VERSION 5.8 ;
BUSBITCHARS "[]" ;
DIVIDERCHAR "/" ;

UNITS
  DATABASE MICRONS 1000 ;
END UNITS

MANUFACTURINGGRID 0.001 ;

# ============================================================================
# ASAP5 / TSMC N5 Technology LEF
# Updated: 12 routing metals (M1-M12) + 11 via layers
# RC values calibrated to TSMC N5 5nm FinFET metal stack
#
# Metal Tiers:
#   Local (M1-M3):      28nm pitch, 14nm width, 36nm thick
#   Intermediate (M4-M6): 40nm pitch, 20nm width, 40nm thick
#   Semi-global (M7-M8): 80nm pitch, 40nm width, 60nm thick
#   Global (M9-M10):    160nm pitch, 80nm width, 100nm thick
#   Top power (M11-M12): 800nm pitch, 400nm width, 800nm thick
#
# RPERSQ = R_per_μm × Width_μm
# CPERSQDIST = C_per_μm / Width_μm (effective area capacitance)
# ============================================================================

# --- Local interconnect: M1-M3 ---

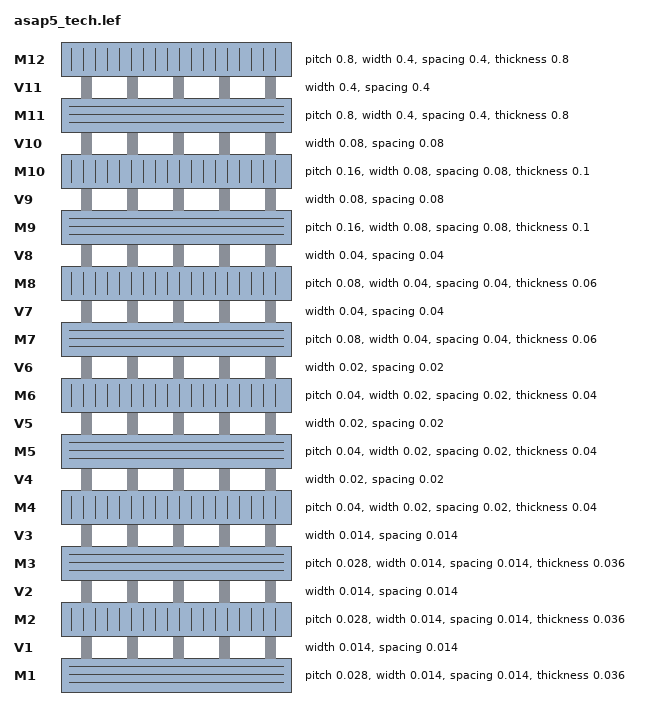
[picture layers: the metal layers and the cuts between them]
LAYER M1
  TYPE ROUTING ;
  DIRECTION HORIZONTAL ;
  PITCH 0.028 ;
  WIDTH 0.014 ;
  SPACING 0.014 ;
  RESISTANCE RPERSQ 0.560 ;
  CAPACITANCE CPERSQDIST 0.02000 ;
  THICKNESS 0.036 ;
END M1

LAYER V1
  TYPE CUT ;
  SPACING 0.014 ;
  WIDTH 0.014 ;
END V1

LAYER M2
  TYPE ROUTING ;
  DIRECTION VERTICAL ;
  PITCH 0.028 ;
  WIDTH 0.014 ;
  SPACING 0.014 ;
  RESISTANCE RPERSQ 3.150 ;
  CAPACITANCE CPERSQDIST 0.01929 ;
  THICKNESS 0.036 ;
END M2

LAYER V2
  TYPE CUT ;
  SPACING 0.014 ;
  WIDTH 0.014 ;
END V2

LAYER M3
  TYPE ROUTING ;
  DIRECTION HORIZONTAL ;
  PITCH 0.028 ;
  WIDTH 0.014 ;
  SPACING 0.014 ;
  RESISTANCE RPERSQ 1.386 ;
  CAPACITANCE CPERSQDIST 0.01571 ;
  THICKNESS 0.036 ;
END M3

LAYER V3
  TYPE CUT ;
  SPACING 0.014 ;
  WIDTH 0.014 ;
END V3

# --- Intermediate interconnect: M4-M6 ---

LAYER M4
  TYPE ROUTING ;
  DIRECTION VERTICAL ;
  PITCH 0.040 ;
  WIDTH 0.020 ;
  SPACING 0.020 ;
  RESISTANCE RPERSQ 2.340 ;
  CAPACITANCE CPERSQDIST 0.01000 ;
  THICKNESS 0.040 ;
END M4

LAYER V4
  TYPE CUT ;
  SPACING 0.020 ;
  WIDTH 0.020 ;
END V4

LAYER M5
  TYPE ROUTING ;
  DIRECTION HORIZONTAL ;
  PITCH 0.040 ;
  WIDTH 0.020 ;
  SPACING 0.020 ;
  RESISTANCE RPERSQ 1.040 ;
  CAPACITANCE CPERSQDIST 0.01300 ;
  THICKNESS 0.040 ;
END M5

LAYER V5
  TYPE CUT ;
  SPACING 0.020 ;
  WIDTH 0.020 ;
END V5

LAYER M6
  TYPE ROUTING ;
  DIRECTION VERTICAL ;
  PITCH 0.040 ;
  WIDTH 0.020 ;
  SPACING 0.020 ;
  RESISTANCE RPERSQ 0.320 ;
  CAPACITANCE CPERSQDIST 0.00800 ;
  THICKNESS 0.040 ;
END M6

LAYER V6
  TYPE CUT ;
  SPACING 0.020 ;
  WIDTH 0.020 ;
END V6

# --- Semi-global interconnect: M7-M8 ---

LAYER M7
  TYPE ROUTING ;
  DIRECTION HORIZONTAL ;
  PITCH 0.080 ;
  WIDTH 0.040 ;
  SPACING 0.040 ;
  RESISTANCE RPERSQ 0.440 ;
  CAPACITANCE CPERSQDIST 0.00425 ;
  THICKNESS 0.060 ;
END M7

LAYER V7
  TYPE CUT ;
  SPACING 0.040 ;
  WIDTH 0.040 ;
END V7

LAYER M8
  TYPE ROUTING ;
  DIRECTION VERTICAL ;
  PITCH 0.080 ;
  WIDTH 0.040 ;
  SPACING 0.040 ;
  RESISTANCE RPERSQ 0.440 ;
  CAPACITANCE CPERSQDIST 0.00425 ;
  THICKNESS 0.060 ;
END M8

LAYER V8
  TYPE CUT ;
  SPACING 0.040 ;
  WIDTH 0.040 ;
END V8

# --- Global interconnect: M9-M10 ---

LAYER M9
  TYPE ROUTING ;
  DIRECTION HORIZONTAL ;
  PITCH 0.160 ;
  WIDTH 0.080 ;
  SPACING 0.080 ;
  RESISTANCE RPERSQ 0.880 ;
  CAPACITANCE CPERSQDIST 0.00238 ;
  THICKNESS 0.100 ;
END M9

LAYER V9
  TYPE CUT ;
  SPACING 0.080 ;
  WIDTH 0.080 ;
END V9

LAYER M10
  TYPE ROUTING ;
  DIRECTION VERTICAL ;
  PITCH 0.160 ;
  WIDTH 0.080 ;
  SPACING 0.080 ;
  RESISTANCE RPERSQ 0.032 ;
  CAPACITANCE CPERSQDIST 0.00438 ;
  THICKNESS 0.100 ;
END M10

LAYER V10
  TYPE CUT ;
  SPACING 0.080 ;
  WIDTH 0.080 ;
END V10

# --- Top-level power: M11-M12 ---

LAYER M11
  TYPE ROUTING ;
  DIRECTION HORIZONTAL ;
  PITCH 0.800 ;
  WIDTH 0.400 ;
  SPACING 0.400 ;
  RESISTANCE RPERSQ 0.160 ;
  CAPACITANCE CPERSQDIST 0.00088 ;
  THICKNESS 0.800 ;
END M11

LAYER V11
  TYPE CUT ;
  SPACING 0.400 ;
  WIDTH 0.400 ;
END V11

LAYER M12
  TYPE ROUTING ;
  DIRECTION VERTICAL ;
  PITCH 0.800 ;
  WIDTH 0.400 ;
  SPACING 0.400 ;
  RESISTANCE RPERSQ 0.160 ;
  CAPACITANCE CPERSQDIST 0.00088 ;
  THICKNESS 0.800 ;
END M12

# ============================================================================
# VIA DEFINITIONS
# ============================================================================

VIA V1_1x1 DEFAULT
  LAYER M1 ;
    RECT -0.007 -0.007 0.007 0.007 ;
  LAYER V1 ;
    RECT -0.007 -0.007 0.007 0.007 ;
  LAYER M2 ;
    RECT -0.007 -0.007 0.007 0.007 ;
END V1_1x1

VIA V2_1x1 DEFAULT
  LAYER M2 ;
    RECT -0.007 -0.007 0.007 0.007 ;
  LAYER V2 ;
    RECT -0.007 -0.007 0.007 0.007 ;
  LAYER M3 ;
    RECT -0.007 -0.007 0.007 0.007 ;
END V2_1x1

VIA V3_1x1 DEFAULT
  LAYER M3 ;
    RECT -0.007 -0.007 0.007 0.007 ;
  LAYER V3 ;
    RECT -0.007 -0.007 0.007 0.007 ;
  LAYER M4 ;
    RECT -0.007 -0.007 0.007 0.007 ;
END V3_1x1

VIA V4_1x1 DEFAULT
  LAYER M4 ;
    RECT -0.010 -0.010 0.010 0.010 ;
  LAYER V4 ;
    RECT -0.010 -0.010 0.010 0.010 ;
  LAYER M5 ;
    RECT -0.010 -0.010 0.010 0.010 ;
END V4_1x1

VIA V5_1x1 DEFAULT
  LAYER M5 ;
    RECT -0.010 -0.010 0.010 0.010 ;
  LAYER V5 ;
    RECT -0.010 -0.010 0.010 0.010 ;
  LAYER M6 ;
    RECT -0.010 -0.010 0.010 0.010 ;
END V5_1x1

VIA V6_1x1 DEFAULT
  LAYER M6 ;
    RECT -0.010 -0.010 0.010 0.010 ;
  LAYER V6 ;
    RECT -0.010 -0.010 0.010 0.010 ;
  LAYER M7 ;
    RECT -0.010 -0.010 0.010 0.010 ;
END V6_1x1

VIA V7_1x1 DEFAULT
  LAYER M7 ;
    RECT -0.020 -0.020 0.020 0.020 ;
  LAYER V7 ;
    RECT -0.020 -0.020 0.020 0.020 ;
  LAYER M8 ;
    RECT -0.020 -0.020 0.020 0.020 ;
END V7_1x1

VIA V8_1x1 DEFAULT
  LAYER M8 ;
    RECT -0.020 -0.020 0.020 0.020 ;
  LAYER V8 ;
    RECT -0.020 -0.020 0.020 0.020 ;
  LAYER M9 ;
    RECT -0.020 -0.020 0.020 0.020 ;
END V8_1x1

VIA V9_1x1 DEFAULT
  LAYER M9 ;
    RECT -0.040 -0.040 0.040 0.040 ;
  LAYER V9 ;
    RECT -0.040 -0.040 0.040 0.040 ;
  LAYER M10 ;
    RECT -0.040 -0.040 0.040 0.040 ;
END V9_1x1

VIA V10_1x1 DEFAULT
  LAYER M10 ;
    RECT -0.040 -0.040 0.040 0.040 ;
  LAYER V10 ;
    RECT -0.040 -0.040 0.040 0.040 ;
  LAYER M11 ;
    RECT -0.040 -0.040 0.040 0.040 ;
END V10_1x1

VIA V11_1x1 DEFAULT
  LAYER M11 ;
    RECT -0.200 -0.200 0.200 0.200 ;
  LAYER V11 ;
    RECT -0.200 -0.200 0.200 0.200 ;
  LAYER M12 ;
    RECT -0.200 -0.200 0.200 0.200 ;
END V11_1x1

# ============================================================================
# VIA GENERATE RULES
# ============================================================================

VIARULE V1_1x1_rule GENERATE
  LAYER M1 ;
    ENCLOSURE 0.000 0.000 ;
  LAYER M2 ;
    ENCLOSURE 0.000 0.000 ;
  LAYER V1 ;
    RECT -0.007 -0.007 0.007 0.007 ;
    SPACING 0.028 BY 0.028 ;
END V1_1x1_rule

VIARULE V2_1x1_rule GENERATE
  LAYER M2 ;
    ENCLOSURE 0.000 0.000 ;
  LAYER M3 ;
    ENCLOSURE 0.000 0.000 ;
  LAYER V2 ;
    RECT -0.007 -0.007 0.007 0.007 ;
    SPACING 0.028 BY 0.028 ;
END V2_1x1_rule

VIARULE V3_1x1_rule GENERATE
  LAYER M3 ;
    ENCLOSURE 0.000 0.000 ;
  LAYER M4 ;
    ENCLOSURE 0.000 0.000 ;
  LAYER V3 ;
    RECT -0.007 -0.007 0.007 0.007 ;
    SPACING 0.028 BY 0.028 ;
END V3_1x1_rule

VIARULE V4_1x1_rule GENERATE
  LAYER M4 ;
    ENCLOSURE 0.000 0.000 ;
  LAYER M5 ;
    ENCLOSURE 0.000 0.000 ;
  LAYER V4 ;
    RECT -0.010 -0.010 0.010 0.010 ;
    SPACING 0.040 BY 0.040 ;
END V4_1x1_rule

VIARULE V5_1x1_rule GENERATE
  LAYER M5 ;
    ENCLOSURE 0.000 0.000 ;
  LAYER M6 ;
    ENCLOSURE 0.000 0.000 ;
  LAYER V5 ;
    RECT -0.010 -0.010 0.010 0.010 ;
    SPACING 0.040 BY 0.040 ;
END V5_1x1_rule

VIARULE V6_1x1_rule GENERATE
  LAYER M6 ;
    ENCLOSURE 0.000 0.000 ;
  LAYER M7 ;
    ENCLOSURE 0.000 0.000 ;
  LAYER V6 ;
    RECT -0.010 -0.010 0.010 0.010 ;
    SPACING 0.040 BY 0.040 ;
END V6_1x1_rule

VIARULE V7_1x1_rule GENERATE
  LAYER M7 ;
    ENCLOSURE 0.000 0.000 ;
  LAYER M8 ;
    ENCLOSURE 0.000 0.000 ;
  LAYER V7 ;
    RECT -0.020 -0.020 0.020 0.020 ;
    SPACING 0.080 BY 0.080 ;
END V7_1x1_rule

VIARULE V8_1x1_rule GENERATE
  LAYER M8 ;
    ENCLOSURE 0.000 0.000 ;
  LAYER M9 ;
    ENCLOSURE 0.000 0.000 ;
  LAYER V8 ;
    RECT -0.020 -0.020 0.020 0.020 ;
    SPACING 0.080 BY 0.080 ;
END V8_1x1_rule

VIARULE V9_1x1_rule GENERATE
  LAYER M9 ;
    ENCLOSURE 0.000 0.000 ;
  LAYER M10 ;
    ENCLOSURE 0.000 0.000 ;
  LAYER V9 ;
    RECT -0.040 -0.040 0.040 0.040 ;
    SPACING 0.160 BY 0.160 ;
END V9_1x1_rule

VIARULE V10_1x1_rule GENERATE
  LAYER M10 ;
    ENCLOSURE 0.000 0.000 ;
  LAYER M11 ;
    ENCLOSURE 0.000 0.000 ;
  LAYER V10 ;
    RECT -0.040 -0.040 0.040 0.040 ;
    SPACING 0.160 BY 0.160 ;
END V10_1x1_rule

VIARULE V11_1x1_rule GENERATE
  LAYER M11 ;
    ENCLOSURE 0.000 0.000 ;
  LAYER M12 ;
    ENCLOSURE 0.000 0.000 ;
  LAYER V11 ;
    RECT -0.200 -0.200 0.200 0.200 ;
    SPACING 0.800 BY 0.800 ;
END V11_1x1_rule

# ============================================================================
# SITE DEFINITION
# ============================================================================

SITE asap5_site
  CLASS CORE ;
  SYMMETRY Y ;
  SIZE 0.044 BY 0.140 ;
END asap5_site

END LIBRARY
